VERSION 5.8 ;
BUSBITCHARS "[]" ;
DIVIDERCHAR "/" ;
UNITS
    DATABASE MICRONS 1000 ;
END UNITS

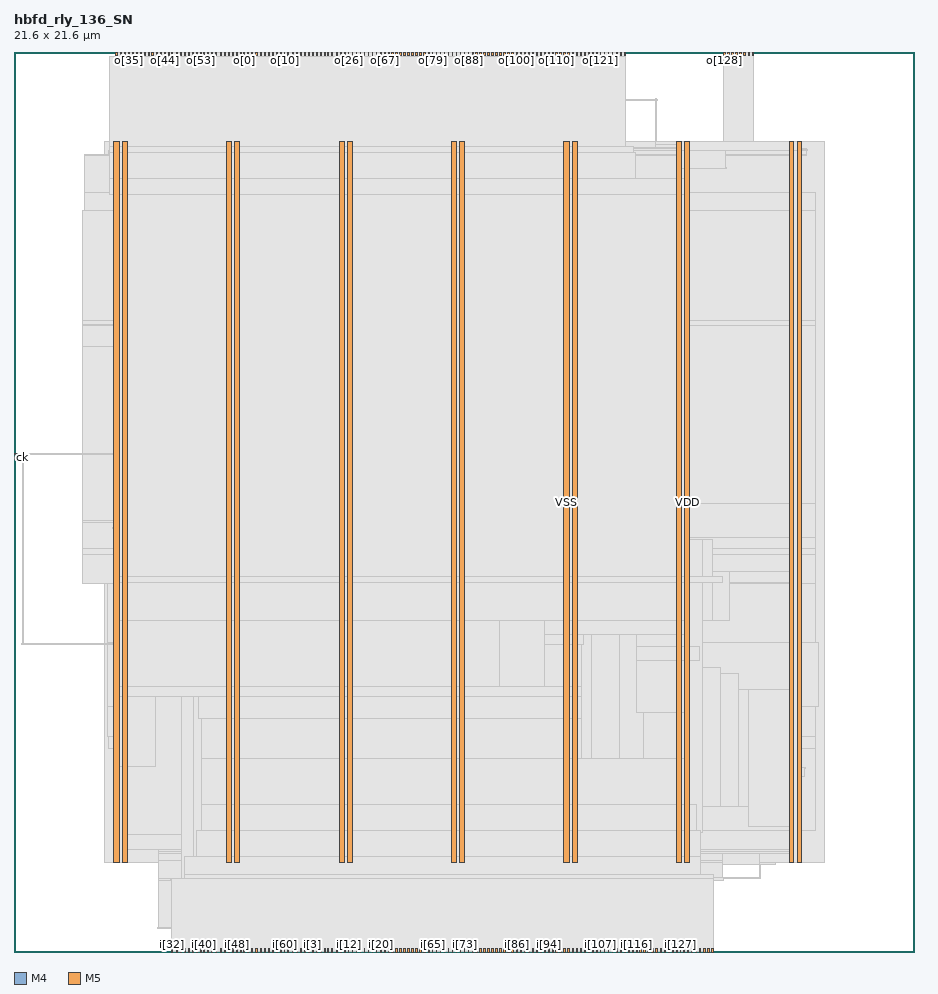
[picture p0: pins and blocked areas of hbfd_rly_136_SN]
MACRO hbfd_rly_136_SN
  FOREIGN hbfd_rly_136_SN 0 0 ;
  CLASS BLOCK ;
  SIZE 21.6 BY 21.6 ;
  PIN ck
    DIRECTION INPUT ;
    USE SIGNAL ;
    PORT
      LAYER M4 ;
        RECT  0 11.856 0.084 11.88 ;
    END
  END ck
  PIN i[0]
    DIRECTION INPUT ;
    USE SIGNAL ;
    PORT
      LAYER M5 ;
        RECT  6.864 0 6.888 0.084 ;
    END
  END i[0]
  PIN i[100]
    DIRECTION INPUT ;
    USE SIGNAL ;
    PORT
      LAYER M5 ;
        RECT  13.392 0 13.416 0.084 ;
    END
  END i[100]
  PIN i[101]
    DIRECTION INPUT ;
    USE SIGNAL ;
    PORT
      LAYER M5 ;
        RECT  13.488 0 13.512 0.084 ;
    END
  END i[101]
  PIN i[102]
    DIRECTION INPUT ;
    USE SIGNAL ;
    PORT
      LAYER M5 ;
        RECT  13.584 0 13.608 0.084 ;
    END
  END i[102]
  PIN i[103]
    DIRECTION INPUT ;
    USE SIGNAL ;
    PORT
      LAYER M5 ;
        RECT  13.68 0 13.704 0.084 ;
    END
  END i[103]
  PIN i[104]
    DIRECTION INPUT ;
    USE SIGNAL ;
    PORT
      LAYER M5 ;
        RECT  13.776 0 13.8 0.084 ;
    END
  END i[104]
  PIN i[105]
    DIRECTION INPUT ;
    USE SIGNAL ;
    PORT
      LAYER M5 ;
        RECT  13.872 0 13.896 0.084 ;
    END
  END i[105]
  PIN i[106]
    DIRECTION INPUT ;
    USE SIGNAL ;
    PORT
      LAYER M5 ;
        RECT  13.968 0 13.992 0.084 ;
    END
  END i[106]
  PIN i[107]
    DIRECTION INPUT ;
    USE SIGNAL ;
    PORT
      LAYER M5 ;
        RECT  14.064 0 14.088 0.084 ;
    END
  END i[107]
  PIN i[108]
    DIRECTION INPUT ;
    USE SIGNAL ;
    PORT
      LAYER M5 ;
        RECT  14.16 0 14.184 0.084 ;
    END
  END i[108]
  PIN i[109]
    DIRECTION INPUT ;
    USE SIGNAL ;
    PORT
      LAYER M5 ;
        RECT  14.256 0 14.28 0.084 ;
    END
  END i[109]
  PIN i[10]
    DIRECTION INPUT ;
    USE SIGNAL ;
    PORT
      LAYER M5 ;
        RECT  7.824 0 7.848 0.084 ;
    END
  END i[10]
  PIN i[110]
    DIRECTION INPUT ;
    USE SIGNAL ;
    PORT
      LAYER M5 ;
        RECT  14.352 0 14.376 0.084 ;
    END
  END i[110]
  PIN i[111]
    DIRECTION INPUT ;
    USE SIGNAL ;
    PORT
      LAYER M5 ;
        RECT  14.448 0 14.472 0.084 ;
    END
  END i[111]
  PIN i[112]
    DIRECTION INPUT ;
    USE SIGNAL ;
    PORT
      LAYER M5 ;
        RECT  14.544 0 14.568 0.084 ;
    END
  END i[112]
  PIN i[113]
    DIRECTION INPUT ;
    USE SIGNAL ;
    PORT
      LAYER M5 ;
        RECT  14.64 0 14.664 0.084 ;
    END
  END i[113]
  PIN i[114]
    DIRECTION INPUT ;
    USE SIGNAL ;
    PORT
      LAYER M5 ;
        RECT  14.736 0 14.76 0.084 ;
    END
  END i[114]
  PIN i[115]
    DIRECTION INPUT ;
    USE SIGNAL ;
    PORT
      LAYER M5 ;
        RECT  14.832 0 14.856 0.084 ;
    END
  END i[115]
  PIN i[116]
    DIRECTION INPUT ;
    USE SIGNAL ;
    PORT
      LAYER M5 ;
        RECT  14.928 0 14.952 0.084 ;
    END
  END i[116]
  PIN i[117]
    DIRECTION INPUT ;
    USE SIGNAL ;
    PORT
      LAYER M5 ;
        RECT  15.024 0 15.048 0.084 ;
    END
  END i[117]
  PIN i[118]
    DIRECTION INPUT ;
    USE SIGNAL ;
    PORT
      LAYER M5 ;
        RECT  15.12 0 15.144 0.084 ;
    END
  END i[118]
  PIN i[119]
    DIRECTION INPUT ;
    USE SIGNAL ;
    PORT
      LAYER M5 ;
        RECT  15.216 0 15.24 0.084 ;
    END
  END i[119]
  PIN i[11]
    DIRECTION INPUT ;
    USE SIGNAL ;
    PORT
      LAYER M5 ;
        RECT  7.92 0 7.944 0.084 ;
    END
  END i[11]
  PIN i[120]
    DIRECTION INPUT ;
    USE SIGNAL ;
    PORT
      LAYER M5 ;
        RECT  15.312 0 15.336 0.084 ;
    END
  END i[120]
  PIN i[121]
    DIRECTION INPUT ;
    USE SIGNAL ;
    PORT
      LAYER M5 ;
        RECT  15.408 0 15.432 0.084 ;
    END
  END i[121]
  PIN i[122]
    DIRECTION INPUT ;
    USE SIGNAL ;
    PORT
      LAYER M5 ;
        RECT  15.504 0 15.528 0.084 ;
    END
  END i[122]
  PIN i[123]
    DIRECTION INPUT ;
    USE SIGNAL ;
    PORT
      LAYER M5 ;
        RECT  15.6 0 15.624 0.084 ;
    END
  END i[123]
  PIN i[124]
    DIRECTION INPUT ;
    USE SIGNAL ;
    PORT
      LAYER M5 ;
        RECT  15.696 0 15.72 0.084 ;
    END
  END i[124]
  PIN i[125]
    DIRECTION INPUT ;
    USE SIGNAL ;
    PORT
      LAYER M5 ;
        RECT  15.792 0 15.816 0.084 ;
    END
  END i[125]
  PIN i[126]
    DIRECTION INPUT ;
    USE SIGNAL ;
    PORT
      LAYER M5 ;
        RECT  15.888 0 15.912 0.084 ;
    END
  END i[126]
  PIN i[127]
    DIRECTION INPUT ;
    USE SIGNAL ;
    PORT
      LAYER M5 ;
        RECT  15.984 0 16.008 0.084 ;
    END
  END i[127]
  PIN i[128]
    DIRECTION INPUT ;
    USE SIGNAL ;
    PORT
      LAYER M5 ;
        RECT  16.08 0 16.104 0.084 ;
    END
  END i[128]
  PIN i[129]
    DIRECTION INPUT ;
    USE SIGNAL ;
    PORT
      LAYER M5 ;
        RECT  16.176 0 16.2 0.084 ;
    END
  END i[129]
  PIN i[12]
    DIRECTION INPUT ;
    USE SIGNAL ;
    PORT
      LAYER M5 ;
        RECT  8.016 0 8.04 0.084 ;
    END
  END i[12]
  PIN i[130]
    DIRECTION INPUT ;
    USE SIGNAL ;
    PORT
      LAYER M5 ;
        RECT  16.272 0 16.296 0.084 ;
    END
  END i[130]
  PIN i[131]
    DIRECTION INPUT ;
    USE SIGNAL ;
    PORT
      LAYER M5 ;
        RECT  16.368 0 16.392 0.084 ;
    END
  END i[131]
  PIN i[132]
    DIRECTION INPUT ;
    USE SIGNAL ;
    PORT
      LAYER M5 ;
        RECT  16.464 0 16.488 0.084 ;
    END
  END i[132]
  PIN i[133]
    DIRECTION INPUT ;
    USE SIGNAL ;
    PORT
      LAYER M5 ;
        RECT  16.56 0 16.584 0.084 ;
    END
  END i[133]
  PIN i[134]
    DIRECTION INPUT ;
    USE SIGNAL ;
    PORT
      LAYER M5 ;
        RECT  16.656 0 16.68 0.084 ;
    END
  END i[134]
  PIN i[135]
    DIRECTION INPUT ;
    USE SIGNAL ;
    PORT
      LAYER M5 ;
        RECT  16.752 0 16.776 0.084 ;
    END
  END i[135]
  PIN i[13]
    DIRECTION INPUT ;
    USE SIGNAL ;
    PORT
      LAYER M5 ;
        RECT  8.112 0 8.136 0.084 ;
    END
  END i[13]
  PIN i[14]
    DIRECTION INPUT ;
    USE SIGNAL ;
    PORT
      LAYER M5 ;
        RECT  8.208 0 8.232 0.084 ;
    END
  END i[14]
  PIN i[15]
    DIRECTION INPUT ;
    USE SIGNAL ;
    PORT
      LAYER M5 ;
        RECT  8.304 0 8.328 0.084 ;
    END
  END i[15]
  PIN i[16]
    DIRECTION INPUT ;
    USE SIGNAL ;
    PORT
      LAYER M5 ;
        RECT  8.4 0 8.424 0.084 ;
    END
  END i[16]
  PIN i[17]
    DIRECTION INPUT ;
    USE SIGNAL ;
    PORT
      LAYER M5 ;
        RECT  8.496 0 8.52 0.084 ;
    END
  END i[17]
  PIN i[18]
    DIRECTION INPUT ;
    USE SIGNAL ;
    PORT
      LAYER M5 ;
        RECT  8.592 0 8.616 0.084 ;
    END
  END i[18]
  PIN i[19]
    DIRECTION INPUT ;
    USE SIGNAL ;
    PORT
      LAYER M5 ;
        RECT  8.688 0 8.712 0.084 ;
    END
  END i[19]
  PIN i[1]
    DIRECTION INPUT ;
    USE SIGNAL ;
    PORT
      LAYER M5 ;
        RECT  6.96 0 6.984 0.084 ;
    END
  END i[1]
  PIN i[20]
    DIRECTION INPUT ;
    USE SIGNAL ;
    PORT
      LAYER M5 ;
        RECT  8.784 0 8.808 0.084 ;
    END
  END i[20]
  PIN i[21]
    DIRECTION INPUT ;
    USE SIGNAL ;
    PORT
      LAYER M5 ;
        RECT  8.88 0 8.904 0.084 ;
    END
  END i[21]
  PIN i[22]
    DIRECTION INPUT ;
    USE SIGNAL ;
    PORT
      LAYER M5 ;
        RECT  8.976 0 9 0.084 ;
    END
  END i[22]
  PIN i[23]
    DIRECTION INPUT ;
    USE SIGNAL ;
    PORT
      LAYER M5 ;
        RECT  9.072 0 9.096 0.084 ;
    END
  END i[23]
  PIN i[24]
    DIRECTION INPUT ;
    USE SIGNAL ;
    PORT
      LAYER M5 ;
        RECT  9.168 0 9.192 0.084 ;
    END
  END i[24]
  PIN i[25]
    DIRECTION INPUT ;
    USE SIGNAL ;
    PORT
      LAYER M5 ;
        RECT  9.264 0 9.288 0.084 ;
    END
  END i[25]
  PIN i[26]
    DIRECTION INPUT ;
    USE SIGNAL ;
    PORT
      LAYER M5 ;
        RECT  9.36 0 9.384 0.084 ;
    END
  END i[26]
  PIN i[27]
    DIRECTION INPUT ;
    USE SIGNAL ;
    PORT
      LAYER M5 ;
        RECT  9.456 0 9.48 0.084 ;
    END
  END i[27]
  PIN i[28]
    DIRECTION INPUT ;
    USE SIGNAL ;
    PORT
      LAYER M5 ;
        RECT  9.552 0 9.576 0.084 ;
    END
  END i[28]
  PIN i[29]
    DIRECTION INPUT ;
    USE SIGNAL ;
    PORT
      LAYER M5 ;
        RECT  9.648 0 9.672 0.084 ;
    END
  END i[29]
  PIN i[2]
    DIRECTION INPUT ;
    USE SIGNAL ;
    PORT
      LAYER M5 ;
        RECT  7.056 0 7.08 0.084 ;
    END
  END i[2]
  PIN i[30]
    DIRECTION INPUT ;
    USE SIGNAL ;
    PORT
      LAYER M5 ;
        RECT  9.744 0 9.768 0.084 ;
    END
  END i[30]
  PIN i[31]
    DIRECTION INPUT ;
    USE SIGNAL ;
    PORT
      LAYER M5 ;
        RECT  9.84 0 9.864 0.084 ;
    END
  END i[31]
  PIN i[32]
    DIRECTION INPUT ;
    USE SIGNAL ;
    PORT
      LAYER M5 ;
        RECT  3.792 0 3.816 0.084 ;
    END
  END i[32]
  PIN i[33]
    DIRECTION INPUT ;
    USE SIGNAL ;
    PORT
      LAYER M5 ;
        RECT  3.888 0 3.912 0.084 ;
    END
  END i[33]
  PIN i[34]
    DIRECTION INPUT ;
    USE SIGNAL ;
    PORT
      LAYER M5 ;
        RECT  3.984 0 4.008 0.084 ;
    END
  END i[34]
  PIN i[35]
    DIRECTION INPUT ;
    USE SIGNAL ;
    PORT
      LAYER M5 ;
        RECT  4.08 0 4.104 0.084 ;
    END
  END i[35]
  PIN i[36]
    DIRECTION INPUT ;
    USE SIGNAL ;
    PORT
      LAYER M5 ;
        RECT  4.176 0 4.2 0.084 ;
    END
  END i[36]
  PIN i[37]
    DIRECTION INPUT ;
    USE SIGNAL ;
    PORT
      LAYER M5 ;
        RECT  4.272 0 4.296 0.084 ;
    END
  END i[37]
  PIN i[38]
    DIRECTION INPUT ;
    USE SIGNAL ;
    PORT
      LAYER M5 ;
        RECT  4.368 0 4.392 0.084 ;
    END
  END i[38]
  PIN i[39]
    DIRECTION INPUT ;
    USE SIGNAL ;
    PORT
      LAYER M5 ;
        RECT  4.464 0 4.488 0.084 ;
    END
  END i[39]
  PIN i[3]
    DIRECTION INPUT ;
    USE SIGNAL ;
    PORT
      LAYER M5 ;
        RECT  7.152 0 7.176 0.084 ;
    END
  END i[3]
  PIN i[40]
    DIRECTION INPUT ;
    USE SIGNAL ;
    PORT
      LAYER M5 ;
        RECT  4.56 0 4.584 0.084 ;
    END
  END i[40]
  PIN i[41]
    DIRECTION INPUT ;
    USE SIGNAL ;
    PORT
      LAYER M5 ;
        RECT  4.656 0 4.68 0.084 ;
    END
  END i[41]
  PIN i[42]
    DIRECTION INPUT ;
    USE SIGNAL ;
    PORT
      LAYER M5 ;
        RECT  4.752 0 4.776 0.084 ;
    END
  END i[42]
  PIN i[43]
    DIRECTION INPUT ;
    USE SIGNAL ;
    PORT
      LAYER M5 ;
        RECT  4.848 0 4.872 0.084 ;
    END
  END i[43]
  PIN i[44]
    DIRECTION INPUT ;
    USE SIGNAL ;
    PORT
      LAYER M5 ;
        RECT  4.944 0 4.968 0.084 ;
    END
  END i[44]
  PIN i[45]
    DIRECTION INPUT ;
    USE SIGNAL ;
    PORT
      LAYER M5 ;
        RECT  5.04 0 5.064 0.084 ;
    END
  END i[45]
  PIN i[46]
    DIRECTION INPUT ;
    USE SIGNAL ;
    PORT
      LAYER M5 ;
        RECT  5.136 0 5.16 0.084 ;
    END
  END i[46]
  PIN i[47]
    DIRECTION INPUT ;
    USE SIGNAL ;
    PORT
      LAYER M5 ;
        RECT  5.232 0 5.256 0.084 ;
    END
  END i[47]
  PIN i[48]
    DIRECTION INPUT ;
    USE SIGNAL ;
    PORT
      LAYER M5 ;
        RECT  5.328 0 5.352 0.084 ;
    END
  END i[48]
  PIN i[49]
    DIRECTION INPUT ;
    USE SIGNAL ;
    PORT
      LAYER M5 ;
        RECT  5.424 0 5.448 0.084 ;
    END
  END i[49]
  PIN i[4]
    DIRECTION INPUT ;
    USE SIGNAL ;
    PORT
      LAYER M5 ;
        RECT  7.248 0 7.272 0.084 ;
    END
  END i[4]
  PIN i[50]
    DIRECTION INPUT ;
    USE SIGNAL ;
    PORT
      LAYER M5 ;
        RECT  5.52 0 5.544 0.084 ;
    END
  END i[50]
  PIN i[51]
    DIRECTION INPUT ;
    USE SIGNAL ;
    PORT
      LAYER M5 ;
        RECT  5.616 0 5.64 0.084 ;
    END
  END i[51]
  PIN i[52]
    DIRECTION INPUT ;
    USE SIGNAL ;
    PORT
      LAYER M5 ;
        RECT  5.712 0 5.736 0.084 ;
    END
  END i[52]
  PIN i[53]
    DIRECTION INPUT ;
    USE SIGNAL ;
    PORT
      LAYER M5 ;
        RECT  5.808 0 5.832 0.084 ;
    END
  END i[53]
  PIN i[54]
    DIRECTION INPUT ;
    USE SIGNAL ;
    PORT
      LAYER M5 ;
        RECT  5.904 0 5.928 0.084 ;
    END
  END i[54]
  PIN i[55]
    DIRECTION INPUT ;
    USE SIGNAL ;
    PORT
      LAYER M5 ;
        RECT  6 0 6.024 0.084 ;
    END
  END i[55]
  PIN i[56]
    DIRECTION INPUT ;
    USE SIGNAL ;
    PORT
      LAYER M5 ;
        RECT  6.096 0 6.12 0.084 ;
    END
  END i[56]
  PIN i[57]
    DIRECTION INPUT ;
    USE SIGNAL ;
    PORT
      LAYER M5 ;
        RECT  6.192 0 6.216 0.084 ;
    END
  END i[57]
  PIN i[58]
    DIRECTION INPUT ;
    USE SIGNAL ;
    PORT
      LAYER M5 ;
        RECT  6.288 0 6.312 0.084 ;
    END
  END i[58]
  PIN i[59]
    DIRECTION INPUT ;
    USE SIGNAL ;
    PORT
      LAYER M5 ;
        RECT  6.384 0 6.408 0.084 ;
    END
  END i[59]
  PIN i[5]
    DIRECTION INPUT ;
    USE SIGNAL ;
    PORT
      LAYER M5 ;
        RECT  7.344 0 7.368 0.084 ;
    END
  END i[5]
  PIN i[60]
    DIRECTION INPUT ;
    USE SIGNAL ;
    PORT
      LAYER M5 ;
        RECT  6.48 0 6.504 0.084 ;
    END
  END i[60]
  PIN i[61]
    DIRECTION INPUT ;
    USE SIGNAL ;
    PORT
      LAYER M5 ;
        RECT  6.576 0 6.6 0.084 ;
    END
  END i[61]
  PIN i[62]
    DIRECTION INPUT ;
    USE SIGNAL ;
    PORT
      LAYER M5 ;
        RECT  6.672 0 6.696 0.084 ;
    END
  END i[62]
  PIN i[63]
    DIRECTION INPUT ;
    USE SIGNAL ;
    PORT
      LAYER M5 ;
        RECT  6.768 0 6.792 0.084 ;
    END
  END i[63]
  PIN i[64]
    DIRECTION INPUT ;
    USE SIGNAL ;
    PORT
      LAYER M5 ;
        RECT  9.936 0 9.96 0.084 ;
    END
  END i[64]
  PIN i[65]
    DIRECTION INPUT ;
    USE SIGNAL ;
    PORT
      LAYER M5 ;
        RECT  10.032 0 10.056 0.084 ;
    END
  END i[65]
  PIN i[66]
    DIRECTION INPUT ;
    USE SIGNAL ;
    PORT
      LAYER M5 ;
        RECT  10.128 0 10.152 0.084 ;
    END
  END i[66]
  PIN i[67]
    DIRECTION INPUT ;
    USE SIGNAL ;
    PORT
      LAYER M5 ;
        RECT  10.224 0 10.248 0.084 ;
    END
  END i[67]
  PIN i[68]
    DIRECTION INPUT ;
    USE SIGNAL ;
    PORT
      LAYER M5 ;
        RECT  10.32 0 10.344 0.084 ;
    END
  END i[68]
  PIN i[69]
    DIRECTION INPUT ;
    USE SIGNAL ;
    PORT
      LAYER M5 ;
        RECT  10.416 0 10.44 0.084 ;
    END
  END i[69]
  PIN i[6]
    DIRECTION INPUT ;
    USE SIGNAL ;
    PORT
      LAYER M5 ;
        RECT  7.44 0 7.464 0.084 ;
    END
  END i[6]
  PIN i[70]
    DIRECTION INPUT ;
    USE SIGNAL ;
    PORT
      LAYER M5 ;
        RECT  10.512 0 10.536 0.084 ;
    END
  END i[70]
  PIN i[71]
    DIRECTION INPUT ;
    USE SIGNAL ;
    PORT
      LAYER M5 ;
        RECT  10.608 0 10.632 0.084 ;
    END
  END i[71]
  PIN i[72]
    DIRECTION INPUT ;
    USE SIGNAL ;
    PORT
      LAYER M5 ;
        RECT  10.704 0 10.728 0.084 ;
    END
  END i[72]
  PIN i[73]
    DIRECTION INPUT ;
    USE SIGNAL ;
    PORT
      LAYER M5 ;
        RECT  10.8 0 10.824 0.084 ;
    END
  END i[73]
  PIN i[74]
    DIRECTION INPUT ;
    USE SIGNAL ;
    PORT
      LAYER M5 ;
        RECT  10.896 0 10.92 0.084 ;
    END
  END i[74]
  PIN i[75]
    DIRECTION INPUT ;
    USE SIGNAL ;
    PORT
      LAYER M5 ;
        RECT  10.992 0 11.016 0.084 ;
    END
  END i[75]
  PIN i[76]
    DIRECTION INPUT ;
    USE SIGNAL ;
    PORT
      LAYER M5 ;
        RECT  11.088 0 11.112 0.084 ;
    END
  END i[76]
  PIN i[77]
    DIRECTION INPUT ;
    USE SIGNAL ;
    PORT
      LAYER M5 ;
        RECT  11.184 0 11.208 0.084 ;
    END
  END i[77]
  PIN i[78]
    DIRECTION INPUT ;
    USE SIGNAL ;
    PORT
      LAYER M5 ;
        RECT  11.28 0 11.304 0.084 ;
    END
  END i[78]
  PIN i[79]
    DIRECTION INPUT ;
    USE SIGNAL ;
    PORT
      LAYER M5 ;
        RECT  11.376 0 11.4 0.084 ;
    END
  END i[79]
  PIN i[7]
    DIRECTION INPUT ;
    USE SIGNAL ;
    PORT
      LAYER M5 ;
        RECT  7.536 0 7.56 0.084 ;
    END
  END i[7]
  PIN i[80]
    DIRECTION INPUT ;
    USE SIGNAL ;
    PORT
      LAYER M5 ;
        RECT  11.472 0 11.496 0.084 ;
    END
  END i[80]
  PIN i[81]
    DIRECTION INPUT ;
    USE SIGNAL ;
    PORT
      LAYER M5 ;
        RECT  11.568 0 11.592 0.084 ;
    END
  END i[81]
  PIN i[82]
    DIRECTION INPUT ;
    USE SIGNAL ;
    PORT
      LAYER M5 ;
        RECT  11.664 0 11.688 0.084 ;
    END
  END i[82]
  PIN i[83]
    DIRECTION INPUT ;
    USE SIGNAL ;
    PORT
      LAYER M5 ;
        RECT  11.76 0 11.784 0.084 ;
    END
  END i[83]
  PIN i[84]
    DIRECTION INPUT ;
    USE SIGNAL ;
    PORT
      LAYER M5 ;
        RECT  11.856 0 11.88 0.084 ;
    END
  END i[84]
  PIN i[85]
    DIRECTION INPUT ;
    USE SIGNAL ;
    PORT
      LAYER M5 ;
        RECT  11.952 0 11.976 0.084 ;
    END
  END i[85]
  PIN i[86]
    DIRECTION INPUT ;
    USE SIGNAL ;
    PORT
      LAYER M5 ;
        RECT  12.048 0 12.072 0.084 ;
    END
  END i[86]
  PIN i[87]
    DIRECTION INPUT ;
    USE SIGNAL ;
    PORT
      LAYER M5 ;
        RECT  12.144 0 12.168 0.084 ;
    END
  END i[87]
  PIN i[88]
    DIRECTION INPUT ;
    USE SIGNAL ;
    PORT
      LAYER M5 ;
        RECT  12.24 0 12.264 0.084 ;
    END
  END i[88]
  PIN i[89]
    DIRECTION INPUT ;
    USE SIGNAL ;
    PORT
      LAYER M5 ;
        RECT  12.336 0 12.36 0.084 ;
    END
  END i[89]
  PIN i[8]
    DIRECTION INPUT ;
    USE SIGNAL ;
    PORT
      LAYER M5 ;
        RECT  7.632 0 7.656 0.084 ;
    END
  END i[8]
  PIN i[90]
    DIRECTION INPUT ;
    USE SIGNAL ;
    PORT
      LAYER M5 ;
        RECT  12.432 0 12.456 0.084 ;
    END
  END i[90]
  PIN i[91]
    DIRECTION INPUT ;
    USE SIGNAL ;
    PORT
      LAYER M5 ;
        RECT  12.528 0 12.552 0.084 ;
    END
  END i[91]
  PIN i[92]
    DIRECTION INPUT ;
    USE SIGNAL ;
    PORT
      LAYER M5 ;
        RECT  12.624 0 12.648 0.084 ;
    END
  END i[92]
  PIN i[93]
    DIRECTION INPUT ;
    USE SIGNAL ;
    PORT
      LAYER M5 ;
        RECT  12.72 0 12.744 0.084 ;
    END
  END i[93]
  PIN i[94]
    DIRECTION INPUT ;
    USE SIGNAL ;
    PORT
      LAYER M5 ;
        RECT  12.816 0 12.84 0.084 ;
    END
  END i[94]
  PIN i[95]
    DIRECTION INPUT ;
    USE SIGNAL ;
    PORT
      LAYER M5 ;
        RECT  12.912 0 12.936 0.084 ;
    END
  END i[95]
  PIN i[96]
    DIRECTION INPUT ;
    USE SIGNAL ;
    PORT
      LAYER M5 ;
        RECT  13.008 0 13.032 0.084 ;
    END
  END i[96]
  PIN i[97]
    DIRECTION INPUT ;
    USE SIGNAL ;
    PORT
      LAYER M5 ;
        RECT  13.104 0 13.128 0.084 ;
    END
  END i[97]
  PIN i[98]
    DIRECTION INPUT ;
    USE SIGNAL ;
    PORT
      LAYER M5 ;
        RECT  13.2 0 13.224 0.084 ;
    END
  END i[98]
  PIN i[99]
    DIRECTION INPUT ;
    USE SIGNAL ;
    PORT
      LAYER M5 ;
        RECT  13.296 0 13.32 0.084 ;
    END
  END i[99]
  PIN i[9]
    DIRECTION INPUT ;
    USE SIGNAL ;
    PORT
      LAYER M5 ;
        RECT  7.728 0 7.752 0.084 ;
    END
  END i[9]
  PIN o[0]
    DIRECTION OUTPUT ;
    USE SIGNAL ;
    PORT
      LAYER M5 ;
        RECT  5.52 21.516 5.544 21.6 ;
    END
  END o[0]
  PIN o[100]
    DIRECTION OUTPUT ;
    USE SIGNAL ;
    PORT
      LAYER M5 ;
        RECT  12.048 21.516 12.072 21.6 ;
    END
  END o[100]
  PIN o[101]
    DIRECTION OUTPUT ;
    USE SIGNAL ;
    PORT
      LAYER M5 ;
        RECT  12.144 21.516 12.168 21.6 ;
    END
  END o[101]
  PIN o[102]
    DIRECTION OUTPUT ;
    USE SIGNAL ;
    PORT
      LAYER M5 ;
        RECT  12.24 21.516 12.264 21.6 ;
    END
  END o[102]
  PIN o[103]
    DIRECTION OUTPUT ;
    USE SIGNAL ;
    PORT
      LAYER M5 ;
        RECT  12.336 21.516 12.36 21.6 ;
    END
  END o[103]
  PIN o[104]
    DIRECTION OUTPUT ;
    USE SIGNAL ;
    PORT
      LAYER M5 ;
        RECT  12.432 21.516 12.456 21.6 ;
    END
  END o[104]
  PIN o[105]
    DIRECTION OUTPUT ;
    USE SIGNAL ;
    PORT
      LAYER M5 ;
        RECT  12.528 21.516 12.552 21.6 ;
    END
  END o[105]
  PIN o[106]
    DIRECTION OUTPUT ;
    USE SIGNAL ;
    PORT
      LAYER M5 ;
        RECT  12.624 21.516 12.648 21.6 ;
    END
  END o[106]
  PIN o[107]
    DIRECTION OUTPUT ;
    USE SIGNAL ;
    PORT
      LAYER M5 ;
        RECT  12.72 21.516 12.744 21.6 ;
    END
  END o[107]
  PIN o[108]
    DIRECTION OUTPUT ;
    USE SIGNAL ;
    PORT
      LAYER M5 ;
        RECT  12.816 21.516 12.84 21.6 ;
    END
  END o[108]
  PIN o[109]
    DIRECTION OUTPUT ;
    USE SIGNAL ;
    PORT
      LAYER M5 ;
        RECT  12.912 21.516 12.936 21.6 ;
    END
  END o[109]
  PIN o[10]
    DIRECTION OUTPUT ;
    USE SIGNAL ;
    PORT
      LAYER M5 ;
        RECT  6.48 21.516 6.504 21.6 ;
    END
  END o[10]
  PIN o[110]
    DIRECTION OUTPUT ;
    USE SIGNAL ;
    PORT
      LAYER M5 ;
        RECT  13.008 21.516 13.032 21.6 ;
    END
  END o[110]
  PIN o[111]
    DIRECTION OUTPUT ;
    USE SIGNAL ;
    PORT
      LAYER M5 ;
        RECT  13.104 21.516 13.128 21.6 ;
    END
  END o[111]
  PIN o[112]
    DIRECTION OUTPUT ;
    USE SIGNAL ;
    PORT
      LAYER M5 ;
        RECT  13.2 21.516 13.224 21.6 ;
    END
  END o[112]
  PIN o[113]
    DIRECTION OUTPUT ;
    USE SIGNAL ;
    PORT
      LAYER M5 ;
        RECT  13.296 21.516 13.32 21.6 ;
    END
  END o[113]
  PIN o[114]
    DIRECTION OUTPUT ;
    USE SIGNAL ;
    PORT
      LAYER M5 ;
        RECT  13.392 21.516 13.416 21.6 ;
    END
  END o[114]
  PIN o[115]
    DIRECTION OUTPUT ;
    USE SIGNAL ;
    PORT
      LAYER M5 ;
        RECT  13.488 21.516 13.512 21.6 ;
    END
  END o[115]
  PIN o[116]
    DIRECTION OUTPUT ;
    USE SIGNAL ;
    PORT
      LAYER M5 ;
        RECT  13.584 21.516 13.608 21.6 ;
    END
  END o[116]
  PIN o[117]
    DIRECTION OUTPUT ;
    USE SIGNAL ;
    PORT
      LAYER M5 ;
        RECT  13.68 21.516 13.704 21.6 ;
    END
  END o[117]
  PIN o[118]
    DIRECTION OUTPUT ;
    USE SIGNAL ;
    PORT
      LAYER M5 ;
        RECT  13.776 21.516 13.8 21.6 ;
    END
  END o[118]
  PIN o[119]
    DIRECTION OUTPUT ;
    USE SIGNAL ;
    PORT
      LAYER M5 ;
        RECT  13.872 21.516 13.896 21.6 ;
    END
  END o[119]
  PIN o[11]
    DIRECTION OUTPUT ;
    USE SIGNAL ;
    PORT
      LAYER M5 ;
        RECT  6.576 21.516 6.6 21.6 ;
    END
  END o[11]
  PIN o[120]
    DIRECTION OUTPUT ;
    USE SIGNAL ;
    PORT
      LAYER M5 ;
        RECT  13.968 21.516 13.992 21.6 ;
    END
  END o[120]
  PIN o[121]
    DIRECTION OUTPUT ;
    USE SIGNAL ;
    PORT
      LAYER M5 ;
        RECT  14.064 21.516 14.088 21.6 ;
    END
  END o[121]
  PIN o[122]
    DIRECTION OUTPUT ;
    USE SIGNAL ;
    PORT
      LAYER M5 ;
        RECT  14.16 21.516 14.184 21.6 ;
    END
  END o[122]
  PIN o[123]
    DIRECTION OUTPUT ;
    USE SIGNAL ;
    PORT
      LAYER M5 ;
        RECT  14.256 21.516 14.28 21.6 ;
    END
  END o[123]
  PIN o[124]
    DIRECTION OUTPUT ;
    USE SIGNAL ;
    PORT
      LAYER M5 ;
        RECT  14.352 21.516 14.376 21.6 ;
    END
  END o[124]
  PIN o[125]
    DIRECTION OUTPUT ;
    USE SIGNAL ;
    PORT
      LAYER M5 ;
        RECT  14.448 21.516 14.472 21.6 ;
    END
  END o[125]
  PIN o[126]
    DIRECTION OUTPUT ;
    USE SIGNAL ;
    PORT
      LAYER M5 ;
        RECT  14.544 21.516 14.568 21.6 ;
    END
  END o[126]
  PIN o[127]
    DIRECTION OUTPUT ;
    USE SIGNAL ;
    PORT
      LAYER M5 ;
        RECT  14.64 21.516 14.664 21.6 ;
    END
  END o[127]
  PIN o[128]
    DIRECTION OUTPUT ;
    USE SIGNAL ;
    PORT
      LAYER M5 ;
        RECT  17.04 21.516 17.064 21.6 ;
    END
  END o[128]
  PIN o[129]
    DIRECTION OUTPUT ;
    USE SIGNAL ;
    PORT
      LAYER M5 ;
        RECT  17.136 21.516 17.16 21.6 ;
    END
  END o[129]
  PIN o[12]
    DIRECTION OUTPUT ;
    USE SIGNAL ;
    PORT
      LAYER M5 ;
        RECT  6.672 21.516 6.696 21.6 ;
    END
  END o[12]
  PIN o[130]
    DIRECTION OUTPUT ;
    USE SIGNAL ;
    PORT
      LAYER M5 ;
        RECT  17.232 21.516 17.256 21.6 ;
    END
  END o[130]
  PIN o[131]
    DIRECTION OUTPUT ;
    USE SIGNAL ;
    PORT
      LAYER M5 ;
        RECT  17.328 21.516 17.352 21.6 ;
    END
  END o[131]
  PIN o[132]
    DIRECTION OUTPUT ;
    USE SIGNAL ;
    PORT
      LAYER M5 ;
        RECT  17.424 21.516 17.448 21.6 ;
    END
  END o[132]
  PIN o[133]
    DIRECTION OUTPUT ;
    USE SIGNAL ;
    PORT
      LAYER M5 ;
        RECT  17.52 21.516 17.544 21.6 ;
    END
  END o[133]
  PIN o[134]
    DIRECTION OUTPUT ;
    USE SIGNAL ;
    PORT
      LAYER M5 ;
        RECT  17.616 21.516 17.64 21.6 ;
    END
  END o[134]
  PIN o[135]
    DIRECTION OUTPUT ;
    USE SIGNAL ;
    PORT
      LAYER M5 ;
        RECT  17.712 21.516 17.736 21.6 ;
    END
  END o[135]
  PIN o[13]
    DIRECTION OUTPUT ;
    USE SIGNAL ;
    PORT
      LAYER M5 ;
        RECT  6.768 21.516 6.792 21.6 ;
    END
  END o[13]
  PIN o[14]
    DIRECTION OUTPUT ;
    USE SIGNAL ;
    PORT
      LAYER M5 ;
        RECT  6.864 21.516 6.888 21.6 ;
    END
  END o[14]
  PIN o[15]
    DIRECTION OUTPUT ;
    USE SIGNAL ;
    PORT
      LAYER M5 ;
        RECT  6.96 21.516 6.984 21.6 ;
    END
  END o[15]
  PIN o[16]
    DIRECTION OUTPUT ;
    USE SIGNAL ;
    PORT
      LAYER M5 ;
        RECT  7.056 21.516 7.08 21.6 ;
    END
  END o[16]
  PIN o[17]
    DIRECTION OUTPUT ;
    USE SIGNAL ;
    PORT
      LAYER M5 ;
        RECT  7.152 21.516 7.176 21.6 ;
    END
  END o[17]
  PIN o[18]
    DIRECTION OUTPUT ;
    USE SIGNAL ;
    PORT
      LAYER M5 ;
        RECT  7.248 21.516 7.272 21.6 ;
    END
  END o[18]
  PIN o[19]
    DIRECTION OUTPUT ;
    USE SIGNAL ;
    PORT
      LAYER M5 ;
        RECT  7.344 21.516 7.368 21.6 ;
    END
  END o[19]
  PIN o[1]
    DIRECTION OUTPUT ;
    USE SIGNAL ;
    PORT
      LAYER M5 ;
        RECT  5.616 21.516 5.64 21.6 ;
    END
  END o[1]
  PIN o[20]
    DIRECTION OUTPUT ;
    USE SIGNAL ;
    PORT
      LAYER M5 ;
        RECT  7.44 21.516 7.464 21.6 ;
    END
  END o[20]
  PIN o[21]
    DIRECTION OUTPUT ;
    USE SIGNAL ;
    PORT
      LAYER M5 ;
        RECT  7.536 21.516 7.56 21.6 ;
    END
  END o[21]
  PIN o[22]
    DIRECTION OUTPUT ;
    USE SIGNAL ;
    PORT
      LAYER M5 ;
        RECT  7.632 21.516 7.656 21.6 ;
    END
  END o[22]
  PIN o[23]
    DIRECTION OUTPUT ;
    USE SIGNAL ;
    PORT
      LAYER M5 ;
        RECT  7.728 21.516 7.752 21.6 ;
    END
  END o[23]
  PIN o[24]
    DIRECTION OUTPUT ;
    USE SIGNAL ;
    PORT
      LAYER M5 ;
        RECT  7.824 21.516 7.848 21.6 ;
    END
  END o[24]
  PIN o[25]
    DIRECTION OUTPUT ;
    USE SIGNAL ;
    PORT
      LAYER M5 ;
        RECT  7.92 21.516 7.944 21.6 ;
    END
  END o[25]
  PIN o[26]
    DIRECTION OUTPUT ;
    USE SIGNAL ;
    PORT
      LAYER M5 ;
        RECT  8.016 21.516 8.04 21.6 ;
    END
  END o[26]
  PIN o[27]
    DIRECTION OUTPUT ;
    USE SIGNAL ;
    PORT
      LAYER M5 ;
        RECT  8.112 21.516 8.136 21.6 ;
    END
  END o[27]
  PIN o[28]
    DIRECTION OUTPUT ;
    USE SIGNAL ;
    PORT
      LAYER M5 ;
        RECT  8.208 21.516 8.232 21.6 ;
    END
  END o[28]
  PIN o[29]
    DIRECTION OUTPUT ;
    USE SIGNAL ;
    PORT
      LAYER M5 ;
        RECT  8.304 21.516 8.328 21.6 ;
    END
  END o[29]
  PIN o[2]
    DIRECTION OUTPUT ;
    USE SIGNAL ;
    PORT
      LAYER M5 ;
        RECT  5.712 21.516 5.736 21.6 ;
    END
  END o[2]
  PIN o[30]
    DIRECTION OUTPUT ;
    USE SIGNAL ;
    PORT
      LAYER M5 ;
        RECT  8.4 21.516 8.424 21.6 ;
    END
  END o[30]
  PIN o[31]
    DIRECTION OUTPUT ;
    USE SIGNAL ;
    PORT
      LAYER M5 ;
        RECT  8.496 21.516 8.52 21.6 ;
    END
  END o[31]
  PIN o[32]
    DIRECTION OUTPUT ;
    USE SIGNAL ;
    PORT
      LAYER M5 ;
        RECT  2.448 21.516 2.472 21.6 ;
    END
  END o[32]
  PIN o[33]
    DIRECTION OUTPUT ;
    USE SIGNAL ;
    PORT
      LAYER M5 ;
        RECT  2.544 21.516 2.568 21.6 ;
    END
  END o[33]
  PIN o[34]
    DIRECTION OUTPUT ;
    USE SIGNAL ;
    PORT
      LAYER M5 ;
        RECT  2.64 21.516 2.664 21.6 ;
    END
  END o[34]
  PIN o[35]
    DIRECTION OUTPUT ;
    USE SIGNAL ;
    PORT
      LAYER M5 ;
        RECT  2.736 21.516 2.76 21.6 ;
    END
  END o[35]
  PIN o[36]
    DIRECTION OUTPUT ;
    USE SIGNAL ;
    PORT
      LAYER M5 ;
        RECT  2.832 21.516 2.856 21.6 ;
    END
  END o[36]
  PIN o[37]
    DIRECTION OUTPUT ;
    USE SIGNAL ;
    PORT
      LAYER M5 ;
        RECT  2.928 21.516 2.952 21.6 ;
    END
  END o[37]
  PIN o[38]
    DIRECTION OUTPUT ;
    USE SIGNAL ;
    PORT
      LAYER M5 ;
        RECT  3.024 21.516 3.048 21.6 ;
    END
  END o[38]
  PIN o[39]
    DIRECTION OUTPUT ;
    USE SIGNAL ;
    PORT
      LAYER M5 ;
        RECT  3.12 21.516 3.144 21.6 ;
    END
  END o[39]
  PIN o[3]
    DIRECTION OUTPUT ;
    USE SIGNAL ;
    PORT
      LAYER M5 ;
        RECT  5.808 21.516 5.832 21.6 ;
    END
  END o[3]
  PIN o[40]
    DIRECTION OUTPUT ;
    USE SIGNAL ;
    PORT
      LAYER M5 ;
        RECT  3.216 21.516 3.24 21.6 ;
    END
  END o[40]
  PIN o[41]
    DIRECTION OUTPUT ;
    USE SIGNAL ;
    PORT
      LAYER M5 ;
        RECT  3.312 21.516 3.336 21.6 ;
    END
  END o[41]
  PIN o[42]
    DIRECTION OUTPUT ;
    USE SIGNAL ;
    PORT
      LAYER M5 ;
        RECT  3.408 21.516 3.432 21.6 ;
    END
  END o[42]
  PIN o[43]
    DIRECTION OUTPUT ;
    USE SIGNAL ;
    PORT
      LAYER M5 ;
        RECT  3.504 21.516 3.528 21.6 ;
    END
  END o[43]
  PIN o[44]
    DIRECTION OUTPUT ;
    USE SIGNAL ;
    PORT
      LAYER M5 ;
        RECT  3.6 21.516 3.624 21.6 ;
    END
  END o[44]
  PIN o[45]
    DIRECTION OUTPUT ;
    USE SIGNAL ;
    PORT
      LAYER M5 ;
        RECT  3.696 21.516 3.72 21.6 ;
    END
  END o[45]
  PIN o[46]
    DIRECTION OUTPUT ;
    USE SIGNAL ;
    PORT
      LAYER M5 ;
        RECT  3.792 21.516 3.816 21.6 ;
    END
  END o[46]
  PIN o[47]
    DIRECTION OUTPUT ;
    USE SIGNAL ;
    PORT
      LAYER M5 ;
        RECT  3.888 21.516 3.912 21.6 ;
    END
  END o[47]
  PIN o[48]
    DIRECTION OUTPUT ;
    USE SIGNAL ;
    PORT
      LAYER M5 ;
        RECT  3.984 21.516 4.008 21.6 ;
    END
  END o[48]
  PIN o[49]
    DIRECTION OUTPUT ;
    USE SIGNAL ;
    PORT
      LAYER M5 ;
        RECT  4.08 21.516 4.104 21.6 ;
    END
  END o[49]
  PIN o[4]
    DIRECTION OUTPUT ;
    USE SIGNAL ;
    PORT
      LAYER M5 ;
        RECT  5.904 21.516 5.928 21.6 ;
    END
  END o[4]
  PIN o[50]
    DIRECTION OUTPUT ;
    USE SIGNAL ;
    PORT
      LAYER M5 ;
        RECT  4.176 21.516 4.2 21.6 ;
    END
  END o[50]
  PIN o[51]
    DIRECTION OUTPUT ;
    USE SIGNAL ;
    PORT
      LAYER M5 ;
        RECT  4.272 21.516 4.296 21.6 ;
    END
  END o[51]
  PIN o[52]
    DIRECTION OUTPUT ;
    USE SIGNAL ;
    PORT
      LAYER M5 ;
        RECT  4.368 21.516 4.392 21.6 ;
    END
  END o[52]
  PIN o[53]
    DIRECTION OUTPUT ;
    USE SIGNAL ;
    PORT
      LAYER M5 ;
        RECT  4.464 21.516 4.488 21.6 ;
    END
  END o[53]
  PIN o[54]
    DIRECTION OUTPUT ;
    USE SIGNAL ;
    PORT
      LAYER M5 ;
        RECT  4.56 21.516 4.584 21.6 ;
    END
  END o[54]
  PIN o[55]
    DIRECTION OUTPUT ;
    USE SIGNAL ;
    PORT
      LAYER M5 ;
        RECT  4.656 21.516 4.68 21.6 ;
    END
  END o[55]
  PIN o[56]
    DIRECTION OUTPUT ;
    USE SIGNAL ;
    PORT
      LAYER M5 ;
        RECT  4.752 21.516 4.776 21.6 ;
    END
  END o[56]
  PIN o[57]
    DIRECTION OUTPUT ;
    USE SIGNAL ;
    PORT
      LAYER M5 ;
        RECT  4.848 21.516 4.872 21.6 ;
    END
  END o[57]
  PIN o[58]
    DIRECTION OUTPUT ;
    USE SIGNAL ;
    PORT
      LAYER M5 ;
        RECT  4.944 21.516 4.968 21.6 ;
    END
  END o[58]
  PIN o[59]
    DIRECTION OUTPUT ;
    USE SIGNAL ;
    PORT
      LAYER M5 ;
        RECT  5.04 21.516 5.064 21.6 ;
    END
  END o[59]
  PIN o[5]
    DIRECTION OUTPUT ;
    USE SIGNAL ;
    PORT
      LAYER M5 ;
        RECT  6 21.516 6.024 21.6 ;
    END
  END o[5]
  PIN o[60]
    DIRECTION OUTPUT ;
    USE SIGNAL ;
    PORT
      LAYER M5 ;
        RECT  5.136 21.516 5.16 21.6 ;
    END
  END o[60]
  PIN o[61]
    DIRECTION OUTPUT ;
    USE SIGNAL ;
    PORT
      LAYER M5 ;
        RECT  5.232 21.516 5.256 21.6 ;
    END
  END o[61]
  PIN o[62]
    DIRECTION OUTPUT ;
    USE SIGNAL ;
    PORT
      LAYER M5 ;
        RECT  5.328 21.516 5.352 21.6 ;
    END
  END o[62]
  PIN o[63]
    DIRECTION OUTPUT ;
    USE SIGNAL ;
    PORT
      LAYER M5 ;
        RECT  5.424 21.516 5.448 21.6 ;
    END
  END o[63]
  PIN o[64]
    DIRECTION OUTPUT ;
    USE SIGNAL ;
    PORT
      LAYER M5 ;
        RECT  8.592 21.516 8.616 21.6 ;
    END
  END o[64]
  PIN o[65]
    DIRECTION OUTPUT ;
    USE SIGNAL ;
    PORT
      LAYER M5 ;
        RECT  8.688 21.516 8.712 21.6 ;
    END
  END o[65]
  PIN o[66]
    DIRECTION OUTPUT ;
    USE SIGNAL ;
    PORT
      LAYER M5 ;
        RECT  8.784 21.516 8.808 21.6 ;
    END
  END o[66]
  PIN o[67]
    DIRECTION OUTPUT ;
    USE SIGNAL ;
    PORT
      LAYER M5 ;
        RECT  8.88 21.516 8.904 21.6 ;
    END
  END o[67]
  PIN o[68]
    DIRECTION OUTPUT ;
    USE SIGNAL ;
    PORT
      LAYER M5 ;
        RECT  8.976 21.516 9 21.6 ;
    END
  END o[68]
  PIN o[69]
    DIRECTION OUTPUT ;
    USE SIGNAL ;
    PORT
      LAYER M5 ;
        RECT  9.072 21.516 9.096 21.6 ;
    END
  END o[69]
  PIN o[6]
    DIRECTION OUTPUT ;
    USE SIGNAL ;
    PORT
      LAYER M5 ;
        RECT  6.096 21.516 6.12 21.6 ;
    END
  END o[6]
  PIN o[70]
    DIRECTION OUTPUT ;
    USE SIGNAL ;
    PORT
      LAYER M5 ;
        RECT  9.168 21.516 9.192 21.6 ;
    END
  END o[70]
  PIN o[71]
    DIRECTION OUTPUT ;
    USE SIGNAL ;
    PORT
      LAYER M5 ;
        RECT  9.264 21.516 9.288 21.6 ;
    END
  END o[71]
  PIN o[72]
    DIRECTION OUTPUT ;
    USE SIGNAL ;
    PORT
      LAYER M5 ;
        RECT  9.36 21.516 9.384 21.6 ;
    END
  END o[72]
  PIN o[73]
    DIRECTION OUTPUT ;
    USE SIGNAL ;
    PORT
      LAYER M5 ;
        RECT  9.456 21.516 9.48 21.6 ;
    END
  END o[73]
  PIN o[74]
    DIRECTION OUTPUT ;
    USE SIGNAL ;
    PORT
      LAYER M5 ;
        RECT  9.552 21.516 9.576 21.6 ;
    END
  END o[74]
  PIN o[75]
    DIRECTION OUTPUT ;
    USE SIGNAL ;
    PORT
      LAYER M5 ;
        RECT  9.648 21.516 9.672 21.6 ;
    END
  END o[75]
  PIN o[76]
    DIRECTION OUTPUT ;
    USE SIGNAL ;
    PORT
      LAYER M5 ;
        RECT  9.744 21.516 9.768 21.6 ;
    END
  END o[76]
  PIN o[77]
    DIRECTION OUTPUT ;
    USE SIGNAL ;
    PORT
      LAYER M5 ;
        RECT  9.84 21.516 9.864 21.6 ;
    END
  END o[77]
  PIN o[78]
    DIRECTION OUTPUT ;
    USE SIGNAL ;
    PORT
      LAYER M5 ;
        RECT  9.936 21.516 9.96 21.6 ;
    END
  END o[78]
  PIN o[79]
    DIRECTION OUTPUT ;
    USE SIGNAL ;
    PORT
      LAYER M5 ;
        RECT  10.032 21.516 10.056 21.6 ;
    END
  END o[79]
  PIN o[7]
    DIRECTION OUTPUT ;
    USE SIGNAL ;
    PORT
      LAYER M5 ;
        RECT  6.192 21.516 6.216 21.6 ;
    END
  END o[7]
  PIN o[80]
    DIRECTION OUTPUT ;
    USE SIGNAL ;
    PORT
      LAYER M5 ;
        RECT  10.128 21.516 10.152 21.6 ;
    END
  END o[80]
  PIN o[81]
    DIRECTION OUTPUT ;
    USE SIGNAL ;
    PORT
      LAYER M5 ;
        RECT  10.224 21.516 10.248 21.6 ;
    END
  END o[81]
  PIN o[82]
    DIRECTION OUTPUT ;
    USE SIGNAL ;
    PORT
      LAYER M5 ;
        RECT  10.32 21.516 10.344 21.6 ;
    END
  END o[82]
  PIN o[83]
    DIRECTION OUTPUT ;
    USE SIGNAL ;
    PORT
      LAYER M5 ;
        RECT  10.416 21.516 10.44 21.6 ;
    END
  END o[83]
  PIN o[84]
    DIRECTION OUTPUT ;
    USE SIGNAL ;
    PORT
      LAYER M5 ;
        RECT  10.512 21.516 10.536 21.6 ;
    END
  END o[84]
  PIN o[85]
    DIRECTION OUTPUT ;
    USE SIGNAL ;
    PORT
      LAYER M5 ;
        RECT  10.608 21.516 10.632 21.6 ;
    END
  END o[85]
  PIN o[86]
    DIRECTION OUTPUT ;
    USE SIGNAL ;
    PORT
      LAYER M5 ;
        RECT  10.704 21.516 10.728 21.6 ;
    END
  END o[86]
  PIN o[87]
    DIRECTION OUTPUT ;
    USE SIGNAL ;
    PORT
      LAYER M5 ;
        RECT  10.8 21.516 10.824 21.6 ;
    END
  END o[87]
  PIN o[88]
    DIRECTION OUTPUT ;
    USE SIGNAL ;
    PORT
      LAYER M5 ;
        RECT  10.896 21.516 10.92 21.6 ;
    END
  END o[88]
  PIN o[89]
    DIRECTION OUTPUT ;
    USE SIGNAL ;
    PORT
      LAYER M5 ;
        RECT  10.992 21.516 11.016 21.6 ;
    END
  END o[89]
  PIN o[8]
    DIRECTION OUTPUT ;
    USE SIGNAL ;
    PORT
      LAYER M5 ;
        RECT  6.288 21.516 6.312 21.6 ;
    END
  END o[8]
  PIN o[90]
    DIRECTION OUTPUT ;
    USE SIGNAL ;
    PORT
      LAYER M5 ;
        RECT  11.088 21.516 11.112 21.6 ;
    END
  END o[90]
  PIN o[91]
    DIRECTION OUTPUT ;
    USE SIGNAL ;
    PORT
      LAYER M5 ;
        RECT  11.184 21.516 11.208 21.6 ;
    END
  END o[91]
  PIN o[92]
    DIRECTION OUTPUT ;
    USE SIGNAL ;
    PORT
      LAYER M5 ;
        RECT  11.28 21.516 11.304 21.6 ;
    END
  END o[92]
  PIN o[93]
    DIRECTION OUTPUT ;
    USE SIGNAL ;
    PORT
      LAYER M5 ;
        RECT  11.376 21.516 11.4 21.6 ;
    END
  END o[93]
  PIN o[94]
    DIRECTION OUTPUT ;
    USE SIGNAL ;
    PORT
      LAYER M5 ;
        RECT  11.472 21.516 11.496 21.6 ;
    END
  END o[94]
  PIN o[95]
    DIRECTION OUTPUT ;
    USE SIGNAL ;
    PORT
      LAYER M5 ;
        RECT  11.568 21.516 11.592 21.6 ;
    END
  END o[95]
  PIN o[96]
    DIRECTION OUTPUT ;
    USE SIGNAL ;
    PORT
      LAYER M5 ;
        RECT  11.664 21.516 11.688 21.6 ;
    END
  END o[96]
  PIN o[97]
    DIRECTION OUTPUT ;
    USE SIGNAL ;
    PORT
      LAYER M5 ;
        RECT  11.76 21.516 11.784 21.6 ;
    END
  END o[97]
  PIN o[98]
    DIRECTION OUTPUT ;
    USE SIGNAL ;
    PORT
      LAYER M5 ;
        RECT  11.856 21.516 11.88 21.6 ;
    END
  END o[98]
  PIN o[99]
    DIRECTION OUTPUT ;
    USE SIGNAL ;
    PORT
      LAYER M5 ;
        RECT  11.952 21.516 11.976 21.6 ;
    END
  END o[99]
  PIN o[9]
    DIRECTION OUTPUT ;
    USE SIGNAL ;
    PORT
      LAYER M5 ;
        RECT  6.384 21.516 6.408 21.6 ;
    END
  END o[9]
  PIN rs
    DIRECTION INPUT ;
    USE SIGNAL ;
    PORT
      LAYER M4 ;
        RECT  0 11.952 0.084 11.976 ;
    END
  END rs
  PIN VDD
    DIRECTION INOUT ;
    USE POWER ;
    PORT
      LAYER M5 ;
        RECT  18.792 2.151 18.912 19.449 ;
        RECT  16.092 2.151 16.212 19.449 ;
        RECT  13.392 2.151 13.512 19.449 ;
        RECT  10.692 2.151 10.812 19.449 ;
        RECT  7.992 2.151 8.112 19.449 ;
        RECT  5.292 2.151 5.412 19.449 ;
        RECT  2.592 2.151 2.712 19.449 ;
    END
  END VDD
  PIN VSS
    DIRECTION INOUT ;
    USE GROUND ;
    PORT
      LAYER M5 ;
        RECT  18.6 2.137 18.72 19.463 ;
        RECT  15.9 2.137 16.02 19.463 ;
        RECT  13.2 2.137 13.32 19.463 ;
        RECT  10.5 2.137 10.62 19.463 ;
        RECT  7.8 2.137 7.92 19.463 ;
        RECT  5.1 2.137 5.22 19.463 ;
        RECT  2.4 2.137 2.52 19.463 ;
    END
  END VSS
  OBS
    LAYER RVTN ;
     RECT  2.16 2.16 19.44 2.295 ;
     RECT  2.16 2.565 19.44 2.835 ;
     RECT  2.16 3.105 19.44 3.375 ;
     RECT  2.16 3.645 19.44 3.915 ;
     RECT  2.16 4.185 19.44 4.455 ;
     RECT  2.16 4.725 19.44 4.995 ;
     RECT  2.16 5.265 19.44 5.535 ;
     RECT  2.16 5.805 19.44 6.075 ;
     RECT  2.16 6.345 19.44 6.615 ;
     RECT  2.16 6.885 19.44 7.155 ;
     RECT  2.16 7.425 19.44 7.695 ;
     RECT  2.16 7.965 19.44 8.235 ;
     RECT  2.16 8.505 19.44 8.775 ;
     RECT  2.16 9.045 19.44 9.315 ;
     RECT  2.16 9.585 19.44 9.855 ;
     RECT  2.16 10.125 19.44 10.395 ;
     RECT  2.16 10.665 19.44 10.935 ;
     RECT  2.16 11.205 19.44 11.475 ;
     RECT  2.16 11.745 19.44 12.015 ;
     RECT  2.16 12.285 19.44 12.555 ;
     RECT  2.16 12.825 19.44 13.095 ;
     RECT  2.16 13.365 19.44 13.635 ;
     RECT  2.16 13.905 19.44 14.175 ;
     RECT  2.16 14.445 19.44 14.715 ;
     RECT  2.16 14.985 19.44 15.255 ;
     RECT  2.16 15.525 19.44 15.795 ;
     RECT  2.16 16.065 19.44 16.335 ;
     RECT  2.16 16.605 19.44 16.875 ;
     RECT  2.16 17.145 19.44 17.415 ;
     RECT  2.16 17.685 19.44 17.955 ;
     RECT  2.16 18.225 19.44 18.495 ;
     RECT  2.16 18.765 19.44 19.035 ;
     RECT  2.16 19.305 19.44 19.44 ;
    LAYER RVTP ;
     RECT  2.16 2.295 19.44 2.565 ;
     RECT  2.16 2.835 19.44 3.105 ;
     RECT  2.16 3.375 19.44 3.645 ;
     RECT  2.16 3.915 19.44 4.185 ;
     RECT  2.16 4.455 19.44 4.725 ;
     RECT  2.16 4.995 19.44 5.265 ;
     RECT  2.16 5.535 19.44 5.805 ;
     RECT  2.16 6.075 19.44 6.345 ;
     RECT  2.16 6.615 19.44 6.885 ;
     RECT  2.16 7.155 19.44 7.425 ;
     RECT  2.16 7.695 19.44 7.965 ;
     RECT  2.16 8.235 19.44 8.505 ;
     RECT  2.16 8.775 19.44 9.045 ;
     RECT  2.16 9.315 19.44 9.585 ;
     RECT  2.16 9.855 19.44 10.125 ;
     RECT  2.16 10.395 19.44 10.665 ;
     RECT  2.16 10.935 19.44 11.205 ;
     RECT  2.16 11.475 19.44 11.745 ;
     RECT  2.16 12.015 19.44 12.285 ;
     RECT  2.16 12.555 19.44 12.825 ;
     RECT  2.16 13.095 19.44 13.365 ;
     RECT  2.16 13.635 19.44 13.905 ;
     RECT  2.16 14.175 19.44 14.445 ;
     RECT  2.16 14.715 19.44 14.985 ;
     RECT  2.16 15.255 19.44 15.525 ;
     RECT  2.16 15.795 19.44 16.065 ;
     RECT  2.16 16.335 19.44 16.605 ;
     RECT  2.16 16.875 19.44 17.145 ;
     RECT  2.16 17.415 19.44 17.685 ;
     RECT  2.16 17.955 19.44 18.225 ;
     RECT  2.16 18.495 19.44 18.765 ;
     RECT  2.16 19.035 19.44 19.305 ;
    LAYER M1 ;
     RECT  2.16 2.151 19.44 19.449 ;
    LAYER M2 ;
     RECT  1.651 8.856 1.687 8.874 ;
     RECT  1.687 8.856 2.16 9 ;
     RECT  1.651 17.766 2.16 17.784 ;
     RECT  1.687 19.116 2.16 19.134 ;
     RECT  2.16 2.151 3.523 19.449 ;
     RECT  3.523 2.106 4.199 19.449 ;
     RECT  4.199 2.151 8.707 19.449 ;
     RECT  8.671 1.152 8.771 1.17 ;
     RECT  8.707 2.106 9.491 19.449 ;
     RECT  9.491 2.151 16.843 19.449 ;
     RECT  16.843 2.106 18.275 19.449 ;
     RECT  18.275 2.151 19.44 19.449 ;
    LAYER M3 ;
     RECT  7.704 0.091 8.406 0.221 ;
     RECT  8.136 0.221 8.406 0.235 ;
     RECT  8.136 0.235 8.55 0.523 ;
     RECT  4.32 0.523 4.338 0.571 ;
     RECT  6.552 0.523 6.57 0.571 ;
     RECT  3.456 0.571 4.338 1.723 ;
     RECT  5.58 0.091 5.598 1.723 ;
     RECT  6.552 0.571 6.714 1.723 ;
     RECT  8.136 0.523 8.766 1.723 ;
     RECT  11.484 0.523 11.502 1.723 ;
     RECT  13.104 1.099 13.122 1.723 ;
     RECT  15.228 1.099 15.246 1.723 ;
     RECT  3.456 1.723 4.806 1.771 ;
     RECT  5.58 1.723 11.502 1.771 ;
     RECT  12.42 1.723 15.246 1.771 ;
     RECT  16.236 1.723 16.254 1.771 ;
     RECT  16.992 1.723 17.01 1.771 ;
     RECT  17.892 1.771 17.91 2.101 ;
     RECT  12.42 1.771 15.354 2.143 ;
     RECT  16.236 1.771 17.01 2.143 ;
     RECT  17.892 2.101 18.27 2.143 ;
     RECT  3.456 1.771 11.502 2.191 ;
     RECT  12.42 2.143 17.01 2.191 ;
     RECT  3.456 2.191 17.01 2.371 ;
     RECT  17.892 2.143 18.705 2.371 ;
     RECT  2.415 2.143 2.505 2.413 ;
     RECT  3.456 2.371 18.705 2.413 ;
     RECT  2.415 2.413 2.697 2.461 ;
     RECT  3.456 2.413 18.897 2.461 ;
     RECT  2.415 2.461 18.897 2.911 ;
     RECT  2.415 2.911 19.242 4.891 ;
     RECT  2.268 4.891 19.242 5.161 ;
     RECT  2.232 5.161 19.242 5.881 ;
     RECT  2.232 5.881 19.314 7.421 ;
     RECT  2.232 7.421 19.242 8.851 ;
     RECT  1.656 8.851 19.242 9.545 ;
     RECT  1.656 9.545 11.106 9.677 ;
     RECT  11.844 9.545 19.242 9.689 ;
     RECT  12.24 9.689 19.242 9.959 ;
     RECT  1.656 9.677 11.034 10.319 ;
     RECT  1.656 10.319 5.598 10.355 ;
     RECT  12.312 9.959 19.242 10.769 ;
     RECT  1.656 10.355 5.397 14.521 ;
     RECT  1.656 14.521 5.526 15.025 ;
     RECT  6.336 10.319 11.034 15.025 ;
     RECT  12.456 10.769 19.242 15.025 ;
     RECT  1.656 15.025 11.034 15.061 ;
     RECT  1.656 15.061 11.25 15.151 ;
     RECT  12.24 15.025 19.242 15.151 ;
     RECT  1.656 15.151 19.242 17.789 ;
     RECT  1.692 17.789 19.242 18.221 ;
     RECT  1.692 18.221 18.897 19.111 ;
     RECT  1.692 19.111 19.026 19.139 ;
     RECT  2.268 19.139 19.026 19.229 ;
     RECT  6.588 19.229 10.89 19.277 ;
     RECT  11.664 19.229 19.026 19.277 ;
     RECT  5.112 19.229 5.706 19.301 ;
     RECT  6.588 19.277 8.37 19.301 ;
     RECT  9.108 19.277 10.89 19.301 ;
     RECT  11.664 19.277 18.774 19.301 ;
     RECT  9.108 19.301 10.854 19.325 ;
     RECT  18.504 19.301 18.774 19.325 ;
     RECT  11.664 19.301 14.562 19.337 ;
     RECT  6.588 19.301 7.905 19.373 ;
     RECT  9.648 19.325 10.854 19.373 ;
     RECT  13.215 19.337 14.562 19.373 ;
     RECT  15.408 19.301 17.658 19.373 ;
     RECT  18.615 19.325 18.774 19.373 ;
     RECT  11.664 19.337 12.222 19.421 ;
     RECT  2.415 19.229 3.33 19.457 ;
     RECT  5.115 19.301 5.706 19.457 ;
     RECT  7.272 19.373 7.905 19.457 ;
     RECT  13.215 19.373 13.554 19.457 ;
     RECT  15.408 19.373 16.005 19.457 ;
     RECT  18.615 19.373 18.705 19.457 ;
     RECT  10.368 19.373 10.854 19.565 ;
     RECT  13.536 19.457 13.554 19.613 ;
     RECT  7.272 19.457 7.29 19.949 ;
     RECT  12.132 19.421 12.222 19.949 ;
     RECT  2.736 19.457 3.33 20.189 ;
     RECT  15.408 19.457 15.426 20.477 ;
     RECT  12.132 19.949 12.15 20.525 ;
     RECT  14.544 19.373 14.562 20.525 ;
     RECT  17.208 19.373 17.586 20.573 ;
     RECT  7.668 21.163 7.686 21.293 ;
     RECT  3.312 20.189 3.33 21.485 ;
     RECT  5.544 19.457 5.706 21.485 ;
     RECT  11.664 21.259 11.682 21.485 ;
     RECT  17.244 20.573 17.586 21.485 ;
    LAYER M4 ;
     RECT  0.06 11.856 0.227 11.976 ;
     RECT  0.181 7.392 2.408 7.416 ;
     RECT  2.365 10.176 2.408 10.2 ;
     RECT  0.227 11.952 2.408 11.976 ;
     RECT  2.293 18.192 2.408 18.216 ;
     RECT  2.408 2.148 2.512 19.452 ;
     RECT  2.293 21.456 2.533 21.48 ;
     RECT  2.512 2.418 2.629 19.452 ;
     RECT  2.629 2.418 2.704 19.56 ;
     RECT  2.704 15.936 2.725 19.56 ;
     RECT  2.533 21.408 2.819 21.48 ;
     RECT  2.725 15.936 2.867 20.184 ;
     RECT  2.867 15.936 3.017 19.944 ;
     RECT  3.017 15.936 3.155 19.416 ;
     RECT  3.155 15.936 3.269 19.368 ;
     RECT  2.819 21.456 3.385 21.48 ;
     RECT  2.704 10.176 3.449 10.872 ;
     RECT  3.269 15.936 3.485 18.984 ;
     RECT  3.761 1.728 4.028 1.752 ;
     RECT  2.704 2.832 4.028 6.312 ;
     RECT  3.925 14.784 4.097 14.808 ;
     RECT  3.445 0.576 4.249 0.6 ;
     RECT  4.028 1.728 4.309 6.312 ;
     RECT  2.704 7.392 4.309 7.416 ;
     RECT  3.485 15.984 4.501 18.984 ;
     RECT  4.309 0.528 4.595 0.552 ;
     RECT  4.309 1.728 4.981 7.416 ;
     RECT  4.981 1.728 5.108 7.752 ;
     RECT  4.501 8.832 5.108 8.856 ;
     RECT  3.449 10.176 5.108 10.2 ;
     RECT  3.829 11.952 5.108 11.976 ;
     RECT  4.501 15.312 5.108 18.984 ;
     RECT  4.885 21.408 5.125 21.432 ;
     RECT  5.108 1.728 5.212 19.452 ;
     RECT  5.125 21.312 5.221 21.432 ;
     RECT  5.212 1.728 5.404 19.182 ;
     RECT  5.221 20.496 5.413 21.432 ;
     RECT  5.404 1.728 5.465 9.096 ;
     RECT  5.404 15.312 5.465 18.984 ;
     RECT  5.413 20.448 5.489 21.432 ;
     RECT  4.885 0.144 5.554 0.504 ;
     RECT  5.554 0.096 5.651 0.504 ;
     RECT  5.651 0.192 5.699 0.504 ;
     RECT  5.489 20.448 5.843 21.48 ;
     RECT  5.843 20.448 5.987 21.432 ;
     RECT  5.465 2.832 6.265 9.096 ;
     RECT  5.465 15.312 6.275 18.84 ;
     RECT  6.275 15.312 6.365 17.688 ;
     RECT  6.265 3.408 6.433 9.096 ;
     RECT  6.365 15.36 6.509 17.688 ;
     RECT  6.275 18.816 6.533 18.84 ;
     RECT  5.987 20.448 6.563 20.52 ;
     RECT  6.433 3.408 6.649 9.144 ;
     RECT  6.277 0.528 6.725 0.6 ;
     RECT  6.649 3.408 6.853 9.672 ;
     RECT  6.725 0.528 6.995 0.552 ;
     RECT  5.465 1.728 7.045 1.8 ;
     RECT  6.533 18.816 7.045 19.368 ;
     RECT  6.853 3.408 7.285 9.72 ;
     RECT  7.045 18.816 7.301 19.944 ;
     RECT  6.509 15.84 7.381 17.688 ;
     RECT  7.285 3.408 7.477 10.152 ;
     RECT  6.421 14.352 7.477 14.376 ;
     RECT  7.381 15.84 7.525 17.736 ;
     RECT  7.301 18.816 7.525 19.452 ;
     RECT  7.477 21.36 7.573 21.384 ;
     RECT  7.573 21.36 7.613 21.432 ;
     RECT  7.525 15.84 7.621 19.452 ;
     RECT  7.613 21.264 7.621 21.432 ;
     RECT  7.669 0.192 7.693 0.216 ;
     RECT  7.621 21.072 7.763 21.432 ;
     RECT  7.045 1.728 7.765 1.848 ;
     RECT  7.765 1.728 7.808 2.04 ;
     RECT  7.477 3.408 7.808 10.2 ;
     RECT  7.477 14.256 7.808 14.376 ;
     RECT  7.621 15.456 7.808 19.452 ;
     RECT  7.808 1.728 7.912 19.452 ;
     RECT  7.693 0.096 8.005 0.216 ;
     RECT  8.005 0.096 8.101 0.36 ;
     RECT  7.912 1.728 8.104 19.272 ;
     RECT  8.104 15.456 8.165 19.272 ;
     RECT  7.763 21.36 8.387 21.432 ;
     RECT  8.104 2.784 8.417 10.2 ;
     RECT  8.101 0.096 8.435 0.408 ;
     RECT  8.435 0.24 8.561 0.408 ;
     RECT  8.417 2.784 8.669 10.152 ;
     RECT  8.387 21.408 8.675 21.432 ;
     RECT  8.732 0.528 8.819 0.552 ;
     RECT  8.165 15.648 9.097 19.272 ;
     RECT  9.097 15.648 9.101 19.32 ;
     RECT  8.104 1.728 9.133 1.8 ;
     RECT  8.669 2.784 9.133 9.816 ;
     RECT  9.101 15.888 9.157 19.32 ;
     RECT  9.133 1.728 9.251 9.816 ;
     RECT  9.251 2.928 10.177 9.816 ;
     RECT  9.157 15.888 10.213 19.368 ;
     RECT  10.213 15.36 10.309 19.368 ;
     RECT  10.261 0.192 10.357 0.216 ;
     RECT  10.177 2.928 10.357 9.864 ;
     RECT  10.261 21.408 10.357 21.432 ;
     RECT  10.357 21.312 10.451 21.432 ;
     RECT  9.251 1.728 10.508 1.8 ;
     RECT  10.357 2.88 10.508 9.864 ;
     RECT  9.853 12 10.508 12.024 ;
     RECT  10.309 13.584 10.508 13.608 ;
     RECT  10.309 15.36 10.508 19.944 ;
     RECT  10.357 0.144 10.547 0.216 ;
     RECT  10.451 21.312 10.547 21.336 ;
     RECT  10.547 0.192 10.739 0.216 ;
     RECT  10.508 1.728 10.804 19.944 ;
     RECT  10.804 13.056 10.829 13.608 ;
     RECT  10.804 1.728 10.865 10.248 ;
     RECT  11.461 21.168 11.557 21.192 ;
     RECT  11.557 21.168 11.602 21.384 ;
     RECT  11.473 0.528 11.603 0.552 ;
     RECT  10.865 2.832 11.651 10.248 ;
     RECT  11.651 2.832 11.657 9.864 ;
     RECT  11.602 21.168 11.699 21.48 ;
     RECT  10.804 15.744 12.037 19.944 ;
     RECT  11.699 21.168 12.037 21.432 ;
     RECT  12.037 15.744 12.044 21.432 ;
     RECT  10.829 13.056 12.083 13.08 ;
     RECT  12.044 15.408 12.131 21.432 ;
     RECT  12.131 15.888 12.161 21.432 ;
     RECT  12.161 15.888 12.233 19.944 ;
     RECT  10.865 1.728 12.325 1.752 ;
     RECT  12.325 1.728 12.373 1.8 ;
     RECT  11.657 3.408 12.769 9.864 ;
     RECT  12.373 1.728 13.093 1.896 ;
     RECT  12.769 3.408 13.093 9.912 ;
     RECT  12.161 21.408 13.189 21.432 ;
     RECT  13.093 1.104 13.208 9.912 ;
     RECT  12.565 13.104 13.208 13.128 ;
     RECT  12.233 15.888 13.208 19.32 ;
     RECT  13.208 1.104 13.381 19.452 ;
     RECT  13.381 1.104 13.427 19.56 ;
     RECT  13.427 1.728 13.429 19.56 ;
     RECT  13.189 21.216 13.429 21.432 ;
     RECT  13.429 1.728 13.504 21.432 ;
     RECT  13.504 1.728 13.619 10.248 ;
     RECT  13.504 13.68 13.619 13.704 ;
     RECT  13.504 16.368 13.619 21.432 ;
     RECT  13.619 16.368 13.667 21.336 ;
     RECT  13.504 12.48 13.763 12.504 ;
     RECT  13.619 3.312 13.859 10.248 ;
     RECT  13.667 16.368 13.859 20.52 ;
     RECT  13.859 16.368 14.105 19.368 ;
     RECT  14.105 16.944 14.285 19.368 ;
     RECT  14.285 17.04 14.501 19.368 ;
     RECT  13.859 3.408 14.537 10.248 ;
     RECT  13.859 20.448 14.573 20.52 ;
     RECT  13.619 1.728 14.645 1.896 ;
     RECT  14.501 17.04 14.867 19.32 ;
     RECT  14.867 17.04 14.915 19.176 ;
     RECT  14.645 1.728 15.217 1.848 ;
     RECT  14.537 3.408 15.301 9.96 ;
     RECT  14.573 20.448 15.437 20.472 ;
     RECT  15.217 1.104 15.443 1.848 ;
     RECT  15.301 2.88 15.445 9.96 ;
     RECT  15.443 1.728 15.908 1.848 ;
     RECT  15.445 2.832 15.908 9.96 ;
     RECT  14.915 17.04 15.908 18.552 ;
     RECT  15.908 1.728 16.012 19.452 ;
     RECT  16.012 1.728 16.204 19.182 ;
     RECT  16.204 1.728 16.301 1.896 ;
     RECT  15.733 0.144 16.355 0.408 ;
     RECT  16.355 0.288 16.403 0.408 ;
     RECT  16.204 2.88 16.517 9.912 ;
     RECT  16.517 7.968 16.769 9.912 ;
     RECT  16.301 1.728 16.787 1.848 ;
     RECT  16.517 3.504 16.949 6.84 ;
     RECT  16.787 1.728 17.021 1.8 ;
     RECT  16.204 18.816 17.093 18.84 ;
     RECT  16.769 7.968 17.165 9.144 ;
     RECT  17.125 21.456 17.197 21.48 ;
     RECT  16.949 3.504 17.381 6.696 ;
     RECT  17.197 20.544 17.597 21.48 ;
     RECT  17.381 3.504 17.629 6.312 ;
     RECT  17.597 20.544 17.651 20.568 ;
     RECT  17.021 1.776 17.921 1.8 ;
     RECT  17.629 3.024 18.608 6.312 ;
     RECT  17.165 8.88 18.608 9.144 ;
     RECT  17.221 19.248 18.608 19.368 ;
     RECT  18.608 2.148 18.712 19.452 ;
     RECT  18.712 2.418 18.904 19.272 ;
     RECT  18.904 4.224 18.965 4.44 ;
     RECT  18.965 4.416 19.001 4.44 ;
     RECT  18.904 19.248 19.037 19.272 ;
    LAYER M5 ;
     RECT  3.792 0.016 16.776 1.763 ;
     RECT  4.08 1.763 16.776 1.859 ;
     RECT  2.4 2.137 2.52 2.151 ;
     RECT  18.6 2.137 18.72 2.151 ;
     RECT  4.08 1.859 16.488 2.291 ;
     RECT  4.368 2.291 16.488 2.915 ;
     RECT  4.512 2.915 16.392 3.539 ;
     RECT  2.4 2.151 2.712 4.453 ;
     RECT  4.512 3.539 16.212 4.643 ;
     RECT  4.512 4.643 13.608 5.605 ;
     RECT  15.12 4.643 16.212 5.749 ;
     RECT  2.4 4.453 3.384 6.133 ;
     RECT  4.416 5.605 13.608 6.133 ;
     RECT  2.4 6.133 13.608 6.371 ;
     RECT  14.928 5.749 16.212 6.997 ;
     RECT  14.928 6.997 16.44 7.331 ;
     RECT  12.72 6.371 13.608 7.381 ;
     RECT  12.72 7.381 13.656 7.621 ;
     RECT  14.928 7.331 16.212 7.621 ;
     RECT  2.4 6.371 11.64 7.957 ;
     RECT  12.72 7.621 16.212 7.957 ;
     RECT  2.4 7.957 16.212 8.869 ;
     RECT  2.4 8.869 17.016 9.011 ;
     RECT  0.192 7.381 0.216 11.891 ;
     RECT  2.4 9.011 16.212 18.181 ;
     RECT  2.304 18.181 16.212 18.563 ;
     RECT  15.9 18.563 16.212 18.805 ;
     RECT  2.304 18.563 14.904 19.187 ;
     RECT  15.9 18.805 17.064 19.237 ;
     RECT  18.6 2.151 18.912 19.237 ;
     RECT  2.304 19.187 14.856 19.331 ;
     RECT  15.9 19.237 18.912 19.449 ;
     RECT  15.9 19.449 16.02 19.463 ;
     RECT  17.04 19.449 18.72 19.463 ;
     RECT  2.304 19.331 14.664 21.491 ;
     RECT  2.448 21.491 14.664 21.584 ;
     RECT  17.04 19.463 17.736 21.584 ;
  END
END hbfd_rly_136_SN
END LIBRARY
